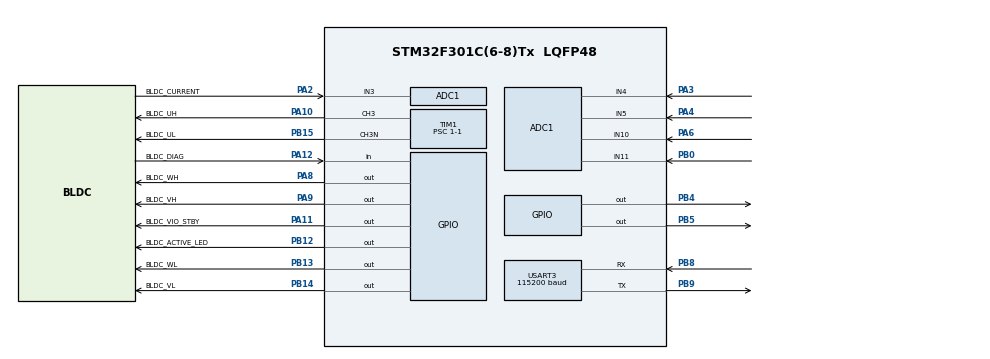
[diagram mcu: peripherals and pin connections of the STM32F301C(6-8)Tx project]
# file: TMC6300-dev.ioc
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ADC1.Channel-0\#ChannelRegularConversion=ADC_CHANNEL_3
ADC1.Channel-1\#ChannelRegularConversion=ADC_CHANNEL_4
ADC1.Channel-2\#ChannelRegularConversion=ADC_CHANNEL_5
ADC1.Channel-3\#ChannelRegularConversion=ADC_CHANNEL_10
ADC1.Channel-4\#ChannelRegularConversion=ADC_CHANNEL_11
ADC1.ContinuousConvMode=ENABLE
ADC1.DMAContinuousRequests=ENABLE
ADC1.NbrOfConversion=5
ADC1.NbrOfConversionFlag=1
ADC1.Offset-0\#ChannelRegularConversion=0
ADC1.Offset-1\#ChannelRegularConversion=0
ADC1.Offset-2\#ChannelRegularConversion=0
ADC1.Offset-3\#ChannelRegularConversion=0
ADC1.Offset-4\#ChannelRegularConversion=0
ADC1.OffsetNumber-0\#ChannelRegularConversion=ADC_OFFSET_NONE
ADC1.OffsetNumber-1\#ChannelRegularConversion=ADC_OFFSET_NONE
ADC1.OffsetNumber-2\#ChannelRegularConversion=ADC_OFFSET_NONE
ADC1.OffsetNumber-3\#ChannelRegularConversion=ADC_OFFSET_NONE
ADC1.OffsetNumber-4\#ChannelRegularConversion=ADC_OFFSET_NONE
ADC1.Rank-0\#ChannelRegularConversion=1
ADC1.Rank-1\#ChannelRegularConversion=2
ADC1.Rank-2\#ChannelRegularConversion=3
ADC1.Rank-3\#ChannelRegularConversion=4
ADC1.Rank-4\#ChannelRegularConversion=5
ADC1.SamplingTime-0\#ChannelRegularConversion=ADC_SAMPLETIME_19CYCLES_5
ADC1.SamplingTime-1\#ChannelRegularConversion=ADC_SAMPLETIME_19CYCLES_5
ADC1.SamplingTime-2\#ChannelRegularConversion=ADC_SAMPLETIME_19CYCLES_5
ADC1.SamplingTime-3\#ChannelRegularConversion=ADC_SAMPLETIME_19CYCLES_5
ADC1.SamplingTime-4\#ChannelRegularConversion=ADC_SAMPLETIME_19CYCLES_5
ADC1.SamplingTimeOPAMP-1\#ChannelRegularConversion=ADC_SAMPLETIME_61CYCLES_5
ADC1.SamplingTimeOPAMP-2\#ChannelRegularConversion=ADC_SAMPLETIME_61CYCLES_5
ADC1.SamplingTimeOPAMP-3\#ChannelRegularConversion=ADC_SAMPLETIME_61CYCLES_5
ADC1.SamplingTimeOPAMP-4\#ChannelRegularConversion=ADC_SAMPLETIME_61CYCLES_5
ADC1.SubFamily=STM32F301x8
ADC1.master=1
Dma.ADC1.0.Direction=DMA_PERIPH_TO_MEMORY
Dma.ADC1.0.Instance=DMA1_Channel1
Dma.ADC1.0.MemDataAlignment=DMA_MDATAALIGN_WORD
Dma.ADC1.0.MemInc=DMA_MINC_ENABLE
Dma.ADC1.0.Mode=DMA_CIRCULAR
Dma.ADC1.0.PeriphDataAlignment=DMA_PDATAALIGN_WORD
Dma.ADC1.0.PeriphInc=DMA_PINC_DISABLE
Dma.ADC1.0.Priority=DMA_PRIORITY_LOW
Dma.Request0=ADC1
Mcu.Family=STM32F3
Mcu.Name=STM32F301C(6-8)Tx
Mcu.Package=LQFP48
NVIC.DMA1_Channel1_IRQn=true\:5\:0\:true\:false\:true\:false\:true\:true
NVIC.PriorityGroup=NVIC_PRIORITYGROUP_4
NVIC.TIM1_TRG_COM_TIM17_IRQn=true\:0\:0\:false\:false\:true\:true\:true\:true
PA10.GPIO_Label=BLDC_UH
PA10.GPIO_Speed=GPIO_SPEED_FREQ_MEDIUM
PA10.Signal=S_TIM1_CH3
PA11.GPIO_Label=BLDC_VIO_STBY
PA11.GPIO_Speed=GPIO_SPEED_FREQ_LOW
PA11.PinState=GPIO_PIN_RESET
PA11.Signal=GPIO_Output
PA12.GPIO_Label=BLDC_DIAG
PA12.Signal=GPIO_Input
PA13.Mode=Trace_Asynchronous_SW
PA13.Signal=SYS_JTMS-SWDIO
PA14.Mode=Trace_Asynchronous_SW
PA14.Signal=SYS_JTCK-SWCLK
PA2.GPIO_Label=BLDC_CURRENT
PA2.Mode=IN3-Single-Ended
PA2.Signal=ADC1_IN3
PA3.Mode=IN4-Single-Ended
PA3.Signal=ADC1_IN4
PA4.Mode=IN5-Single-Ended
PA4.Signal=ADC1_IN5
PA6.Signal=ADCx_IN10
PA8.GPIO_Label=BLDC_WH
PA8.Signal=GPIO_Output
PA9.GPIO_Label=BLDC_VH
PA9.Signal=GPIO_Output
PB0.Mode=IN11-Single-Ended
PB0.Signal=ADC1_IN11
PB12.GPIO_Label=BLDC_ACTIVE_LED
PB12.PinState=GPIO_PIN_RESET
PB12.Signal=GPIO_Output
PB13.GPIO_Label=BLDC_WL
PB13.PinState=GPIO_PIN_SET
PB13.Signal=GPIO_Output
PB14.GPIO_Label=BLDC_VL
PB14.PinState=GPIO_PIN_SET
PB14.Signal=GPIO_Output
PB15.GPIO_Label=BLDC_UL
PB15.GPIO_Speed=GPIO_SPEED_FREQ_MEDIUM
PB15.Mode=PWM Generation3 CH3 CH3N
PB15.Signal=TIM1_CH3N
PB3.Mode=Trace_Asynchronous_SW
PB3.Signal=SYS_JTDO-TRACESWO
PB4.Signal=GPIO_Output
PB5.Signal=GPIO_Output
PB8.Mode=Asynchronous
PB8.Signal=USART3_RX
PB9.Mode=Asynchronous
PB9.Signal=USART3_TX
PF0-OSC_IN.Mode=HSE-External-Oscillator
PF0-OSC_IN.Signal=RCC_OSC_IN
PF1-OSC_OUT.Mode=HSE-External-Oscillator
PF1-OSC_OUT.Signal=RCC_OSC_OUT
ProjectManager.HeapSize=0x200
ProjectManager.StackSize=0x400
ProjectManager.TargetToolchain=STM32CubeIDE
RCC.ADC12PRES=RCC_ADC1PLLCLK_DIV16
RCC.AHBFreq_Value=72000000
RCC.APB1CLKDivider=RCC_HCLK_DIV2
RCC.APB1Freq_Value=36000000
RCC.APB1TimFreq_Value=72000000
RCC.APB2Freq_Value=72000000
RCC.APB2TimCLKDivider=2
RCC.APB2TimFreq_Value=144000000
RCC.CortexFreq_Value=72000000
RCC.HCLKFreq_Value=72000000
RCC.HSE_VALUE=16000000
RCC.HSI_VALUE=8000000
RCC.LSE_VALUE=32768
RCC.PLLSourceVirtual=RCC_PLLSOURCE_HSE
RCC.SYSCLKFreq_VALUE=72000000
RCC.SYSCLKSourceVirtual=RCC_SYSCLKSOURCE_PLLCLK
SH.ADCx_IN10.0=ADC1_IN10,IN10-Single-Ended
SH.S_TIM1_CH3.0=TIM1_CH3,PWM Generation3 CH3 CH3N
TIM1.AutoReloadPreload=TIM_AUTORELOAD_PRELOAD_ENABLE
TIM1.AutomaticOutput=TIM_AUTOMATICOUTPUT_DISABLE
TIM1.Channel-PWM\ Generation1\ CH1\ CH1N=TIM_CHANNEL_1
TIM1.Channel-PWM\ Generation2\ CH2\ CH2N=TIM_CHANNEL_2
TIM1.Channel-PWM\ Generation3\ CH3\ CH3N=TIM_CHANNEL_3
TIM1.CounterMode=TIM_COUNTERMODE_UP
TIM1.DeadTime=0
TIM1.OC1Preload_PWM=ENABLE
TIM1.OCFastMode_PWM-PWM\ Generation1\ CH1\ CH1N=TIM_OCFAST_DISABLE
TIM1.OCFastMode_PWM-PWM\ Generation2\ CH2\ CH2N=TIM_OCFAST_DISABLE
TIM1.OCFastMode_PWM-PWM\ Generation3\ CH3\ CH3N=TIM_OCFAST_DISABLE
TIM1.OCMode_PWM-PWM\ Generation1\ CH1\ CH1N=TIM_OCMODE_PWM1
TIM1.OCMode_PWM-PWM\ Generation2\ CH2\ CH2N=TIM_OCMODE_PWM1
TIM1.OCMode_PWM-PWM\ Generation3\ CH3\ CH3N=TIM_OCMODE_PWM1
TIM1.OCNPolarity_1=TIM_OCNPOLARITY_HIGH
TIM1.OCNPolarity_2=TIM_OCNPOLARITY_HIGH
TIM1.OCNPolarity_3=TIM_OCNPOLARITY_HIGH
TIM1.OCPolarity_1=TIM_OCPOLARITY_HIGH
TIM1.OCPolarity_2=TIM_OCPOLARITY_HIGH
TIM1.OCPolarity_3=TIM_OCPOLARITY_HIGH
TIM1.Period=250-1
TIM1.Prescaler=1-1
TIM1.Pulse-PWM\ Generation1\ CH1\ CH1N=0
TIM1.Pulse-PWM\ Generation2\ CH2\ CH2N=0
TIM1.Pulse-PWM\ Generation3\ CH3\ CH3N=0
USART3.BaudRate=115200
USART3.VirtualMode-Asynchronous=VM_ASYNC
VP_TIM1_VS_ClockSourceINT.Mode=Internal
board=custom

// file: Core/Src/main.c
/* USER CODE BEGIN Header */
/**
 ******************************************************************************
 * @file           : main.c
 * @brief          : Main program body
 ******************************************************************************
 * @attention
 *
 * Copyright (c) 2022 STMicroelectronics.
 * All rights reserved.
 *
 * This software is licensed under terms that can be found in the LICENSE file
 * in the root directory of this software component.
 * If no LICENSE file comes with this software, it is provided AS-IS.
 *
 ******************************************************************************
 */
/* USER CODE END Header */
#include "main.h"

/* USER CODE BEGIN Includes */
#include "TMC6300.h"
#include <stdlib.h>
#include <string.h>
#include <stdio.h>

/* USER CODE END Includes */

ADC_HandleTypeDef hadc1;
DMA_HandleTypeDef hdma_adc1;

TIM_HandleTypeDef htim1;

UART_HandleTypeDef huart3;

/* USER CODE BEGIN PV */
TMC6300_t bldc;
uint32_t adc_dma_buffer[5];
/* USER CODE END PV */

void SystemClock_Config(void);
static void MX_GPIO_Init(void);
static void MX_DMA_Init(void);
static void MX_ADC1_Init(void);
static void MX_TIM1_Init(void);
static void MX_USART3_UART_Init(void);

/* USER CODE BEGIN 0 */

// diag interrupt callback
void HAL_GPIO_EXTI_Callback(uint16_t GPIO_Pin)
{
	// diagnostics callback
	TMC6300_DiagCallback(&bldc, GPIO_Pin);
}

/* USER CODE END 0 */

int main(void)
{

  /* MCU Configuration--------------------------------------------------------*/

  /* Reset of all peripherals, Initializes the Flash interface and the Systick. */
  HAL_Init();

  /* Configure the system clock */
  SystemClock_Config();

  /* Initialize all configured peripherals */
  MX_GPIO_Init();
  MX_DMA_Init();
  MX_ADC1_Init();
  MX_TIM1_Init();
  MX_USART3_UART_Init();
  /* USER CODE BEGIN 2 */

	HAL_Delay(500);

	// bldc init
	TMC6300_Init(&bldc,
			&htim1,
			TIM_CHANNEL_1,
			TIM_CHANNEL_2,
			TIM_CHANNEL_3,
			BLDC_VIO_STBY_GPIO_Port,
			BLDC_VIO_STBY_Pin,
			BLDC_DIAG_GPIO_Port,
			BLDC_DIAG_Pin);

	TMC6300_Enable(&bldc);

	HAL_Delay(100);

	uint16_t power = 25;
	for(; power<2000; power++)
	{
		TMC6300_SetPhaseAngle(&bldc, 0, power);
		if(HAL_GPIO_ReadPin(BLDC_DIAG_GPIO_Port, BLDC_DIAG_Pin))
		{
			HAL_GPIO_WritePin(BLDC_ACTIVE_LED_GPIO_Port, BLDC_ACTIVE_LED_Pin, GPIO_PIN_SET);
			break;
		}
		HAL_Delay(500);
	}

	power -= 10;
	TMC6300_SetPhaseAngle(&bldc, 0, power);

	// reset
	TMC6300_Disable(&bldc);
	HAL_Delay(1000);
	TMC6300_Enable(&bldc);
	HAL_Delay(200);
	HAL_GPIO_WritePin(BLDC_ACTIVE_LED_GPIO_Port, BLDC_ACTIVE_LED_Pin, GPIO_PIN_RESET);

	for(; power<200; power++)
	{
		TMC6300_SetPhaseAngle(&bldc, 0, power);
		if(HAL_GPIO_ReadPin(BLDC_DIAG_GPIO_Port, BLDC_DIAG_Pin))
		{
			HAL_GPIO_WritePin(BLDC_ACTIVE_LED_GPIO_Port, BLDC_ACTIVE_LED_Pin, GPIO_PIN_SET);
			break;
		}
		HAL_Delay(400);
	}

	power -= 20;
	TMC6300_SetPhaseAngle(&bldc, 0, power);

	// reset
	TMC6300_Disable(&bldc);
	HAL_Delay(1000);
	TMC6300_Enable(&bldc);
	HAL_Delay(400);
	HAL_GPIO_WritePin(BLDC_ACTIVE_LED_GPIO_Port, BLDC_ACTIVE_LED_Pin, GPIO_PIN_RESET);

	uint32_t arcsecond = 0;

  /* USER CODE END 2 */

  /* Infinite loop */
  /* USER CODE BEGIN WHILE */
	while (1)
	{
		TMC6300_SetPhaseAngle(&bldc, arcsecond, power);
		arcsecond += 450;
		for(uint32_t i=0; i<125; i++);

//		if(HAL_GPIO_ReadPin(BLDC_DIAG_GPIO_Port, BLDC_DIAG_Pin))
//			HAL_GPIO_WritePin(BLDC_ACTIVE_LED_GPIO_Port, BLDC_ACTIVE_LED_Pin, GPIO_PIN_SET);

    /* USER CODE END WHILE */

	}
}

void SystemClock_Config(void)
{
  RCC_OscInitTypeDef RCC_OscInitStruct = {0};
  RCC_ClkInitTypeDef RCC_ClkInitStruct = {0};
  RCC_PeriphCLKInitTypeDef PeriphClkInit = {0};

  /** Initializes the RCC Oscillators according to the specified parameters
  * in the RCC_OscInitTypeDef structure.
  */
  RCC_OscInitStruct.OscillatorType = RCC_OSCILLATORTYPE_HSE;
  RCC_OscInitStruct.HSEState = RCC_HSE_ON;
  RCC_OscInitStruct.HSEPredivValue = RCC_HSE_PREDIV_DIV1;
  RCC_OscInitStruct.HSIState = RCC_HSI_ON;
  RCC_OscInitStruct.PLL.PLLState = RCC_PLL_ON;
  RCC_OscInitStruct.PLL.PLLSource = RCC_PLLSOURCE_HSE;
  RCC_OscInitStruct.PLL.PLLMUL = RCC_PLL_MUL2;
  if (HAL_RCC_OscConfig(&RCC_OscInitStruct) != HAL_OK)
  {
    Error_Handler();
  }

  /** Initializes the CPU, AHB and APB buses clocks
  */
  RCC_ClkInitStruct.ClockType = RCC_CLOCKTYPE_HCLK|RCC_CLOCKTYPE_SYSCLK
                              |RCC_CLOCKTYPE_PCLK1|RCC_CLOCKTYPE_PCLK2;
  RCC_ClkInitStruct.SYSCLKSource = RCC_SYSCLKSOURCE_PLLCLK;
  RCC_ClkInitStruct.AHBCLKDivider = RCC_SYSCLK_DIV1;
  RCC_ClkInitStruct.APB1CLKDivider = RCC_HCLK_DIV2;
  RCC_ClkInitStruct.APB2CLKDivider = RCC_HCLK_DIV1;

  if (HAL_RCC_ClockConfig(&RCC_ClkInitStruct, FLASH_LATENCY_2) != HAL_OK)
  {
    Error_Handler();
  }
  PeriphClkInit.PeriphClockSelection = RCC_PERIPHCLK_TIM1|RCC_PERIPHCLK_ADC1;
  PeriphClkInit.Tim1ClockSelection = RCC_TIM1CLK_HCLK;
  PeriphClkInit.Adc1ClockSelection = RCC_ADC1PLLCLK_DIV16;

  if (HAL_RCCEx_PeriphCLKConfig(&PeriphClkInit) != HAL_OK)
  {
    Error_Handler();
  }
}

static void MX_ADC1_Init(void)
{

  ADC_ChannelConfTypeDef sConfig = {0};

  /** Common config
  */
  hadc1.Instance = ADC1;
  hadc1.Init.ClockPrescaler = ADC_CLOCK_ASYNC_DIV1;
  hadc1.Init.Resolution = ADC_RESOLUTION_12B;
  hadc1.Init.ScanConvMode = ADC_SCAN_ENABLE;
  hadc1.Init.ContinuousConvMode = ENABLE;
  hadc1.Init.DiscontinuousConvMode = DISABLE;
  hadc1.Init.ExternalTrigConvEdge = ADC_EXTERNALTRIGCONVEDGE_NONE;
  hadc1.Init.ExternalTrigConv = ADC_SOFTWARE_START;
  hadc1.Init.DataAlign = ADC_DATAALIGN_RIGHT;
  hadc1.Init.NbrOfConversion = 5;
  hadc1.Init.DMAContinuousRequests = ENABLE;
  hadc1.Init.EOCSelection = ADC_EOC_SINGLE_CONV;
  hadc1.Init.LowPowerAutoWait = DISABLE;
  hadc1.Init.Overrun = ADC_OVR_DATA_OVERWRITTEN;
  if (HAL_ADC_Init(&hadc1) != HAL_OK)
  {
    Error_Handler();
  }

  /** Configure Regular Channel
  */
  sConfig.Channel = ADC_CHANNEL_3;
  sConfig.Rank = ADC_REGULAR_RANK_1;
  sConfig.SingleDiff = ADC_SINGLE_ENDED;
  sConfig.SamplingTime = ADC_SAMPLETIME_19CYCLES_5;
  sConfig.OffsetNumber = ADC_OFFSET_NONE;
  sConfig.Offset = 0;
  if (HAL_ADC_ConfigChannel(&hadc1, &sConfig) != HAL_OK)
  {
    Error_Handler();
  }

  /** Configure Regular Channel
  */
  sConfig.Channel = ADC_CHANNEL_4;
  sConfig.Rank = ADC_REGULAR_RANK_2;
  if (HAL_ADC_ConfigChannel(&hadc1, &sConfig) != HAL_OK)
  {
    Error_Handler();
  }

  /** Configure Regular Channel
  */
  sConfig.Channel = ADC_CHANNEL_5;
  sConfig.Rank = ADC_REGULAR_RANK_3;
  if (HAL_ADC_ConfigChannel(&hadc1, &sConfig) != HAL_OK)
  {
    Error_Handler();
  }

  /** Configure Regular Channel
  */
  sConfig.Channel = ADC_CHANNEL_10;
  sConfig.Rank = ADC_REGULAR_RANK_4;
  if (HAL_ADC_ConfigChannel(&hadc1, &sConfig) != HAL_OK)
  {
    Error_Handler();
  }

  /** Configure Regular Channel
  */
  sConfig.Channel = ADC_CHANNEL_11;
  sConfig.Rank = ADC_REGULAR_RANK_5;
  if (HAL_ADC_ConfigChannel(&hadc1, &sConfig) != HAL_OK)
  {
    Error_Handler();
  }

}

static void MX_TIM1_Init(void)
{

  TIM_ClockConfigTypeDef sClockSourceConfig = {0};
  TIM_MasterConfigTypeDef sMasterConfig = {0};
  TIM_OC_InitTypeDef sConfigOC = {0};
  TIM_BreakDeadTimeConfigTypeDef sBreakDeadTimeConfig = {0};

  htim1.Instance = TIM1;
  htim1.Init.Prescaler = 1-1;
  htim1.Init.CounterMode = TIM_COUNTERMODE_UP;
  htim1.Init.Period = 250-1;
  htim1.Init.ClockDivision = TIM_CLOCKDIVISION_DIV1;
  htim1.Init.RepetitionCounter = 0;
  htim1.Init.AutoReloadPreload = TIM_AUTORELOAD_PRELOAD_ENABLE;
  if (HAL_TIM_Base_Init(&htim1) != HAL_OK)
  {
    Error_Handler();
  }
  sClockSourceConfig.ClockSource = TIM_CLOCKSOURCE_INTERNAL;
  if (HAL_TIM_ConfigClockSource(&htim1, &sClockSourceConfig) != HAL_OK)
  {
    Error_Handler();
  }
  if (HAL_TIM_PWM_Init(&htim1) != HAL_OK)
  {
    Error_Handler();
  }
  sMasterConfig.MasterOutputTrigger = TIM_TRGO_RESET;
  sMasterConfig.MasterOutputTrigger2 = TIM_TRGO2_RESET;
  sMasterConfig.MasterSlaveMode = TIM_MASTERSLAVEMODE_DISABLE;
  if (HAL_TIMEx_MasterConfigSynchronization(&htim1, &sMasterConfig) != HAL_OK)
  {
    Error_Handler();
  }
  sConfigOC.OCMode = TIM_OCMODE_PWM1;
  sConfigOC.Pulse = 0;
  sConfigOC.OCPolarity = TIM_OCPOLARITY_HIGH;
  sConfigOC.OCNPolarity = TIM_OCNPOLARITY_HIGH;
  sConfigOC.OCFastMode = TIM_OCFAST_DISABLE;
  sConfigOC.OCIdleState = TIM_OCIDLESTATE_RESET;
  sConfigOC.OCNIdleState = TIM_OCNIDLESTATE_RESET;
  if (HAL_TIM_PWM_ConfigChannel(&htim1, &sConfigOC, TIM_CHANNEL_3) != HAL_OK)
  {
    Error_Handler();
  }
  sBreakDeadTimeConfig.OffStateRunMode = TIM_OSSR_DISABLE;
  sBreakDeadTimeConfig.OffStateIDLEMode = TIM_OSSI_DISABLE;
  sBreakDeadTimeConfig.LockLevel = TIM_LOCKLEVEL_OFF;
  sBreakDeadTimeConfig.DeadTime = 0;
  sBreakDeadTimeConfig.BreakState = TIM_BREAK_DISABLE;
  sBreakDeadTimeConfig.BreakPolarity = TIM_BREAKPOLARITY_HIGH;
  sBreakDeadTimeConfig.BreakFilter = 0;
  sBreakDeadTimeConfig.Break2State = TIM_BREAK2_DISABLE;
  sBreakDeadTimeConfig.Break2Polarity = TIM_BREAK2POLARITY_HIGH;
  sBreakDeadTimeConfig.Break2Filter = 0;
  sBreakDeadTimeConfig.AutomaticOutput = TIM_AUTOMATICOUTPUT_DISABLE;
  if (HAL_TIMEx_ConfigBreakDeadTime(&htim1, &sBreakDeadTimeConfig) != HAL_OK)
  {
    Error_Handler();
  }
  HAL_TIM_MspPostInit(&htim1);

}

static void MX_USART3_UART_Init(void)
{

  huart3.Instance = USART3;
  huart3.Init.BaudRate = 115200;
  huart3.Init.WordLength = UART_WORDLENGTH_8B;
  huart3.Init.StopBits = UART_STOPBITS_1;
  huart3.Init.Parity = UART_PARITY_NONE;
  huart3.Init.Mode = UART_MODE_TX_RX;
  huart3.Init.HwFlowCtl = UART_HWCONTROL_NONE;
  huart3.Init.OverSampling = UART_OVERSAMPLING_16;
  huart3.Init.OneBitSampling = UART_ONE_BIT_SAMPLE_DISABLE;
  huart3.AdvancedInit.AdvFeatureInit = UART_ADVFEATURE_NO_INIT;
  if (HAL_UART_Init(&huart3) != HAL_OK)
  {
    Error_Handler();
  }

}

static void MX_DMA_Init(void)
{

  /* DMA controller clock enable */
  __HAL_RCC_DMA1_CLK_ENABLE();

  /* DMA interrupt init */
  /* DMA1_Channel1_IRQn interrupt configuration */
  HAL_NVIC_SetPriority(DMA1_Channel1_IRQn, 5, 0);
  HAL_NVIC_EnableIRQ(DMA1_Channel1_IRQn);

}

static void MX_GPIO_Init(void)
{
  GPIO_InitTypeDef GPIO_InitStruct = {0};

  /* GPIO Ports Clock Enable */
  __HAL_RCC_GPIOF_CLK_ENABLE();
  __HAL_RCC_GPIOA_CLK_ENABLE();
  __HAL_RCC_GPIOB_CLK_ENABLE();

  /*Configure GPIO pin Output Level */
  HAL_GPIO_WritePin(GPIOB, BLDC_ACTIVE_LED_Pin|GPIO_PIN_4|GPIO_PIN_5, GPIO_PIN_RESET);

  /*Configure GPIO pin Output Level */
  HAL_GPIO_WritePin(GPIOB, BLDC_WL_Pin|BLDC_VL_Pin, GPIO_PIN_SET);

  /*Configure GPIO pin Output Level */
  HAL_GPIO_WritePin(GPIOA, BLDC_WH_Pin|BLDC_VH_Pin|BLDC_VIO_STBY_Pin, GPIO_PIN_RESET);

  /*Configure GPIO pins : BLDC_ACTIVE_LED_Pin BLDC_WL_Pin BLDC_VL_Pin PB4
                           PB5 */
  GPIO_InitStruct.Pin = BLDC_ACTIVE_LED_Pin|BLDC_WL_Pin|BLDC_VL_Pin|GPIO_PIN_4
                          |GPIO_PIN_5;
  GPIO_InitStruct.Mode = GPIO_MODE_OUTPUT_PP;
  GPIO_InitStruct.Pull = GPIO_NOPULL;
  GPIO_InitStruct.Speed = GPIO_SPEED_FREQ_LOW;
  HAL_GPIO_Init(GPIOB, &GPIO_InitStruct);

  /*Configure GPIO pins : BLDC_WH_Pin BLDC_VH_Pin BLDC_VIO_STBY_Pin */
  GPIO_InitStruct.Pin = BLDC_WH_Pin|BLDC_VH_Pin|BLDC_VIO_STBY_Pin;
  GPIO_InitStruct.Mode = GPIO_MODE_OUTPUT_PP;
  GPIO_InitStruct.Pull = GPIO_NOPULL;
  GPIO_InitStruct.Speed = GPIO_SPEED_FREQ_LOW;
  HAL_GPIO_Init(GPIOA, &GPIO_InitStruct);

  /*Configure GPIO pin : BLDC_DIAG_Pin */
  GPIO_InitStruct.Pin = BLDC_DIAG_Pin;
  GPIO_InitStruct.Mode = GPIO_MODE_INPUT;
  GPIO_InitStruct.Pull = GPIO_NOPULL;
  HAL_GPIO_Init(BLDC_DIAG_GPIO_Port, &GPIO_InitStruct);

}

void Error_Handler(void)
{
	__disable_irq();
	while (1)
	{
	}
}
